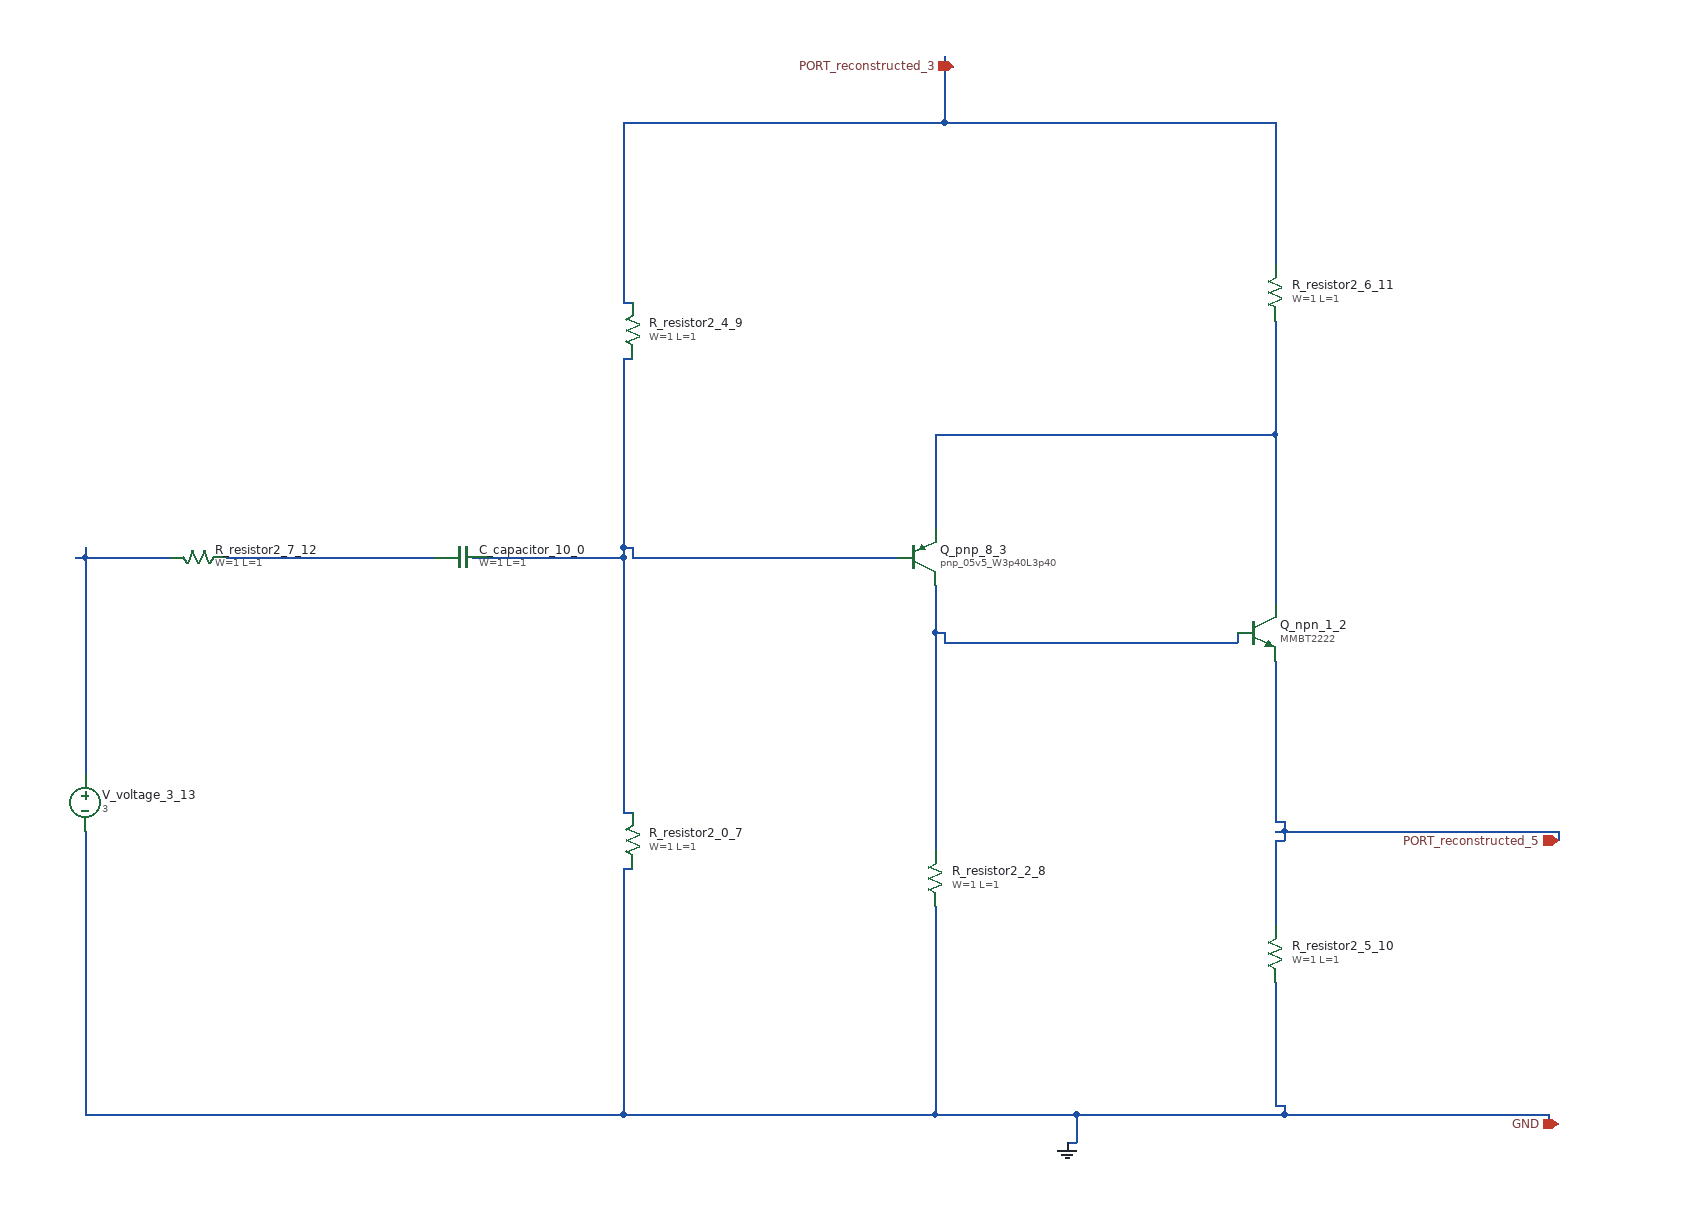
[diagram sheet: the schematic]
v {xschem version=3.4.8 file_version=1.2}
G {}
K {}
V {}
S {}
E {}
C {sky130_fd_pr/cap_mim_m3_1.sym} 660 580 1 0 {name="C_capacitor_10_0" model=cap_mim_m3_1 W=1 L=1 MF=1 spiceprefix=X}
C {devices/gnd.sym} 1300 1200 0 0 {name="l_gnd_9_1" lab="GND"}
C {devices/npn.sym} 1500 660 0 0 {name="Q_npn_1_2"
model=MMBT2222
device=MMBT2222
footprint=SOT23
area=1
m=1}
C {sky130_fd_pr/pnp_05v5.sym} 1140 580 0 0 {name="Q_pnp_8_3"
model=pnp_05v5_W3p40L3p40
m=1
spiceprefix=X
}
C {devices/ipin.sym} 1820 880 0 0 {name="p_port_11_4" lab="PORT_reconstructed_5"}
C {devices/ipin.sym} 1820 1180 0 0 {name="p_port_12_5" lab="GND"}
C {devices/ipin.sym} 1180 60 0 0 {name="p_port_13_6" lab="PORT_reconstructed_3"}
C {sky130_fd_pr/res_generic_po.sym} 840 880 2 0 {name="R_resistor2_0_7"
W=1
L=1
model=res_generic_po
spiceprefix=X
mult=1}
C {sky130_fd_pr/res_generic_po.sym} 1160 920 2 0 {name="R_resistor2_2_8"
W=1
L=1
model=res_generic_po
spiceprefix=X
mult=1}
C {sky130_fd_pr/res_generic_po.sym} 840 340 2 0 {name="R_resistor2_4_9"
W=1
L=1
model=res_generic_po
spiceprefix=X
mult=1}
C {sky130_fd_pr/res_generic_po.sym} 1520 1000 2 0 {name="R_resistor2_5_10"
W=1
L=1
model=res_generic_po
spiceprefix=X
mult=1}
C {sky130_fd_pr/res_generic_po.sym} 1520 300 2 0 {name="R_resistor2_6_11"
W=1
L=1
model=res_generic_po
spiceprefix=X
mult=1}
C {sky130_fd_pr/res_generic_po.sym} 380 580 1 0 {name="R_resistor2_7_12"
W=1
L=1
model=res_generic_po
spiceprefix=X
mult=1}
C {devices/vsource.sym} 260 840 0 0 {name="V_voltage_3_13" value=3 savecurrent=false}
N 410 580 630 580 {}
N 830 850 840 850 {}
N 670 580 690 580 {}
N 690 580 830 580 {}
N 840 580 1120 580 {}
N 830 570 840 570 {}
N 830 370 840 370 {}
N 830 850 830 580 {}
N 830 580 830 570 {}
N 830 570 830 370 {}
N 840 580 840 570 {}
N 1300 1200 1310 1200 {}
N 1810 1180 1820 1180 {}
N 260 1170 830 1170 {}
N 830 1170 1160 1170 {}
N 1160 1170 1310 1170 {}
N 1310 1170 1530 1170 {}
N 1530 1170 1810 1170 {}
N 1520 1160 1530 1160 {}
N 830 910 840 910 {}
N 260 1170 260 870 {}
N 830 1170 830 910 {}
N 1160 1170 1160 950 {}
N 1310 1200 1310 1170 {}
N 1520 1160 1520 1030 {}
N 1530 1170 1530 1160 {}
N 1810 1180 1810 1170 {}
N 830 310 840 310 {}
N 830 120 1170 120 {}
N 1170 120 1520 120 {}
N 1170 60 1180 60 {}
N 830 310 830 120 {}
N 1170 120 1170 60 {}
N 1170 60 1170 50 {}
N 1520 270 1520 120 {}
N 1170 670 1480 670 {}
N 1160 660 1170 660 {}
N 1160 890 1160 660 {}
N 1160 660 1160 610 {}
N 1170 670 1170 660 {}
N 1480 670 1480 660 {}
N 1520 880 1530 880 {}
N 1520 870 1530 870 {}
N 1530 870 1820 870 {}
N 1520 860 1530 860 {}
N 1520 970 1520 880 {}
N 1520 860 1520 690 {}
N 1530 880 1530 870 {}
N 1530 870 1530 860 {}
N 1820 880 1820 870 {}
N 1160 450 1520 450 {}
N 1160 550 1160 450 {}
N 1520 630 1520 450 {}
N 1520 450 1520 330 {}
N 250 580 260 580 {}
N 260 580 350 580 {}
N 260 810 260 580 {}
N 260 580 260 570 {}
